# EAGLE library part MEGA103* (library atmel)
MICROCONTROLLER Low-voltage (L) 128 Kbytes FLASH 4 Kbytes SRAM 2 Kbytes EEPROM UART RTC 8-channel 10 bit ADC

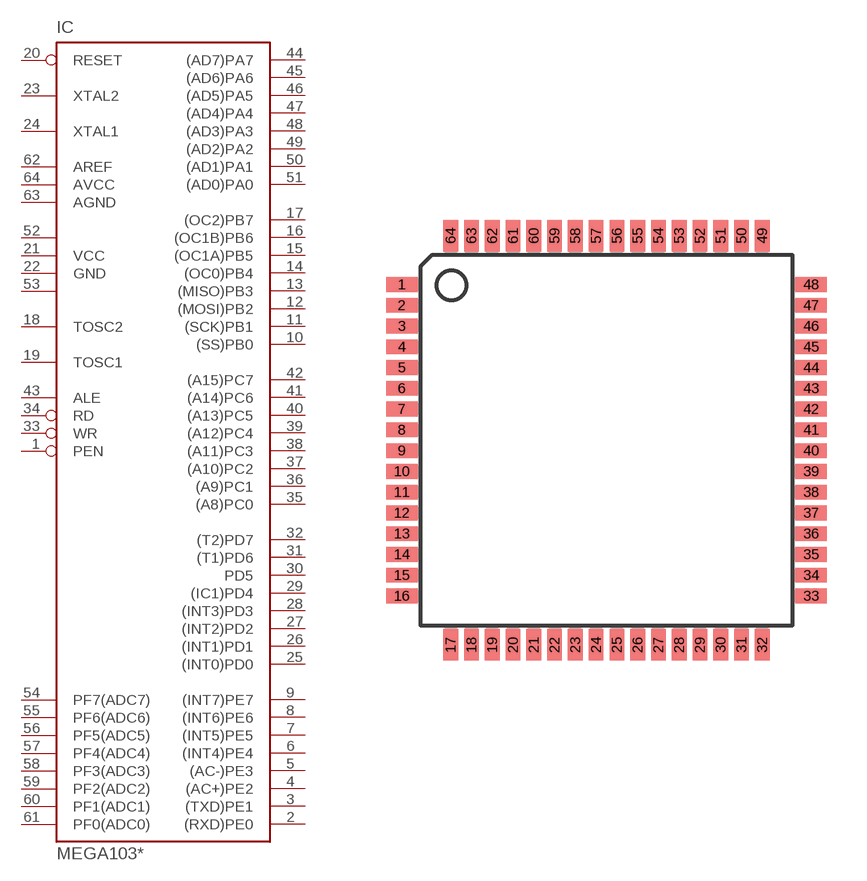
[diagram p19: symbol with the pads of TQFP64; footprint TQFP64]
Designator prefix IC

## MEGA103, MEGA103L  [TQFP64]
1  PEN  in
2  (RXD)PE0
3  (TXD)PE1
4  (AC+)PE2
5  (AC-)PE3
6  (INT4)PE4
7  (INT5)PE5
8  (INT6)PE6
9  (INT7)PE7
10  (SS)PB0
11  (SCK)PB1
12  (MOSI)PB2
13  (MISO)PB3
14  (OC0)PB4
15  (OC1A)PB5
16  (OC1B)PB6
17  (OC2)PB7
18  TOSC2
19  TOSC1
20  RESET  in
21  VCC  pwr
22  GND  pwr
23  XTAL2
24  XTAL1
25  (INT0)PD0
26  (INT1)PD1
27  (INT2)PD2
28  (INT3)PD3
29  (IC1)PD4
30  PD5
31  (T1)PD6
32  (T2)PD7
33  WR
34  RD
35  (A8)PC0  out
36  (A9)PC1  out
37  (A10)PC2  out
38  (A11)PC3  out
39  (A12)PC4  out
40  (A13)PC5  out
41  (A14)PC6  out
42  (A15)PC7  out
43  ALE
44  (AD7)PA7
45  (AD6)PA6
46  (AD5)PA5
47  (AD4)PA4
48  (AD3)PA3
49  (AD2)PA2
50  (AD1)PA1
51  (AD0)PA0
52  VCC1  pwr
53  GND1  pwr
54  PF7(ADC7)  in
55  PF6(ADC6)  in
56  PF5(ADC5)  in
57  PF4(ADC4)  in
58  PF3(ADC3)  in
59  PF2(ADC2)  in
60  PF1(ADC1)  in
61  PF0(ADC0)  in
62  AREF
63  AGND
64  AVCC

## Footprint TQFP64 (pad centres in mm)
Thin Plasic Quad Flat Package
smd 1.194 x 0.559: 1 -7.76,5.905; 2 -7.76,5.118; 3 -7.76,4.331; 4 -7.76,3.543; 5 -7.76,2.756; 6 -7.76,1.968; 7 -7.76,1.181; 8 -7.76,0.394; 9 -7.76,-0.394; 10 -7.76,-1.181; 11 -7.76,-1.968; 12 -7.76,-2.756; 13 -7.76,-3.543; 14 -7.76,-4.331; 15 -7.76,-5.118; 16 -7.76,-5.905; 33 7.76,-5.905; 34 7.76,-5.118; 35 7.76,-4.331; 36 7.76,-3.543; 37 7.76,-2.756; 38 7.76,-1.968; 39 7.76,-1.181; 40 7.76,-0.394; 41 7.76,0.394; 42 7.76,1.181; 43 7.76,1.968; 44 7.76,2.756; 45 7.76,3.543; 46 7.76,4.331; 47 7.76,5.118; 48 7.76,5.905
smd 0.559 x 1.194: 17 -5.905,-7.76; 18 -5.118,-7.76; 19 -4.331,-7.76; 20 -3.543,-7.76; 21 -2.756,-7.76; 22 -1.968,-7.76; 23 -1.181,-7.76; 24 -0.394,-7.76; 25 0.394,-7.76; 26 1.181,-7.76; 27 1.968,-7.76; 28 2.756,-7.76; 29 3.543,-7.76; 30 4.331,-7.76; 31 5.118,-7.76; 32 5.905,-7.76; 49 5.905,7.76; 50 5.118,7.76; 51 4.331,7.76; 52 3.543,7.76; 53 2.756,7.76; 54 1.968,7.76; 55 1.181,7.76; 56 0.394,7.76; 57 -0.394,7.76; 58 -1.181,7.76; 59 -1.968,7.76; 60 -2.756,7.76; 61 -3.543,7.76; 62 -4.331,7.76; 63 -5.118,7.76; 64 -5.905,7.76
